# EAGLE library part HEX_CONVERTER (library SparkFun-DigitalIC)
74HC4050 Hex Buffer Level Shifter SMD SO016

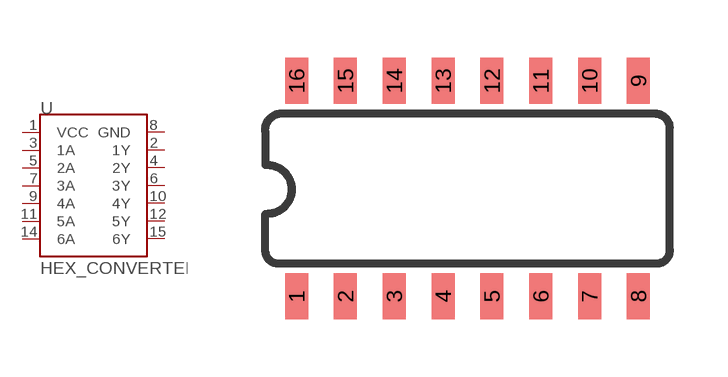
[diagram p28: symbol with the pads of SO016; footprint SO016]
Designator prefix U

## HEX_CONVERTER (PROD_ID: IC-09604)  [SO016]
1  VCC
2  1Y
3  1A
4  2Y
5  2A
6  3Y
7  3A
8  GND
9  4A
10  4Y
11  5A
12  5Y
14  6A
15  6Y

## Footprint SO016 (pad centres in mm)
smd 0.6 x 1.2: 1 -4.445,-2.8; 2 -3.175,-2.8; 3 -1.905,-2.8; 4 -0.635,-2.8; 5 0.635,-2.8; 6 1.905,-2.8; 7 3.175,-2.8; 8 4.445,-2.8; 9 4.445,2.8; 10 3.175,2.8; 11 1.905,2.8; 12 0.635,2.8; 13 -0.635,2.8; 14 -1.905,2.8; 15 -3.175,2.8; 16 -4.445,2.8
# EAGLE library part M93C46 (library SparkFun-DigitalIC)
1kbit SPI EEPROM

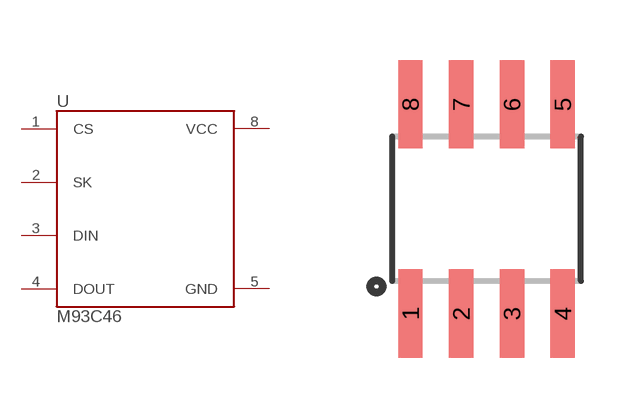
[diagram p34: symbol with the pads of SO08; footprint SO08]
Designator prefix -

## M93C46  [SO08]
1  CS
2  SK
3  DIN
4  DOUT
5  GND
8  VCC

## Footprint SO08 (pad centres in mm)
Small Outline Package Fits JEDEC packages (narrow SOIC-8)
smd 0.61 x 2.21: 1 -1.905,-2.616; 2 -0.635,-2.616; 3 0.635,-2.616; 4 1.905,-2.616; 5 1.905,2.616; 6 0.635,2.616; 7 -0.635,2.616; 8 -1.905,2.616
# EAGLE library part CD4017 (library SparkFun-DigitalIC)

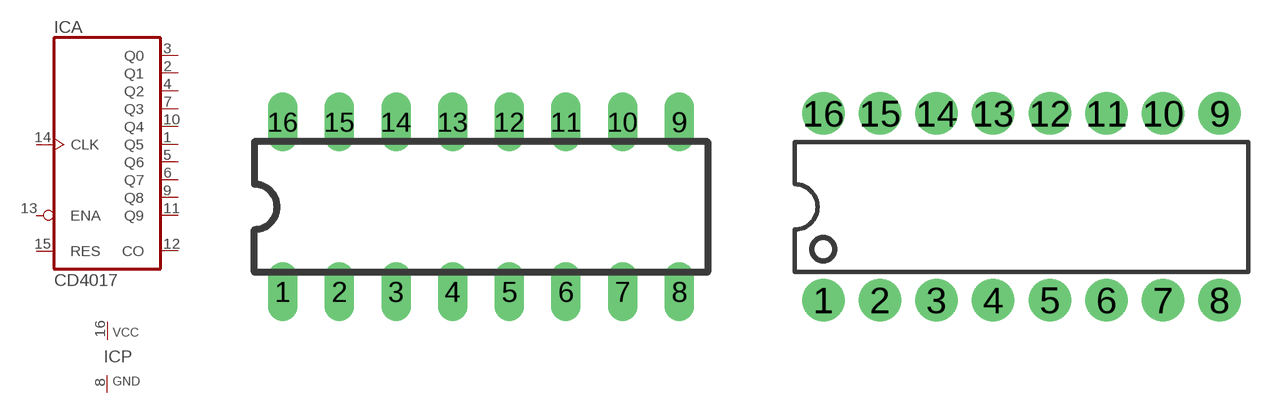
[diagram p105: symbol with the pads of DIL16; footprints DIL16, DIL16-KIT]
Designator prefix IC; gates A=CD4017 P=PWRN

## CD4017 (PROD_ID: IC-11929; VALUE: CD4017)  [DIL16]
1  A:Q5  out
2  A:Q1  out
3  A:Q0  out
4  A:Q2  out
5  A:Q6  out
6  A:Q7  out
7  A:Q3  out
8  P:GND  pwr
9  A:Q8  out
10  A:Q4  out
11  A:Q9  out
12  A:CO  out
13  A:ENA  in
14  A:CLK  in
15  A:RES  in
16  P:VCC  pwr

## CD4017KIT (PROD_ID: IC-11929)  [DIL16-KIT]
Pads as for DIL16

## Footprint DIL16 (pad centres in mm)
Dual In Line Package
drill 0.813 long: 1 -8.89,-3.81; 2 -6.35,-3.81; 3 -3.81,-3.81; 4 -1.27,-3.81; 5 1.27,-3.81; 6 3.81,-3.81; 7 6.35,-3.81; 8 8.89,-3.81; 9 8.89,3.81; 10 6.35,3.81; 11 3.81,3.81; 12 1.27,3.81; 13 -1.27,3.81; 14 -3.81,3.81; 15 -6.35,3.81; 16 -8.89,3.81

## Footprint DIL16-KIT (pad centres in mm)
drill 0.864 pad 1.905: 1 -8.89,-4.191; 2 -6.35,-4.191; 3 -3.81,-4.191; 4 -1.27,-4.191; 5 1.27,-4.191; 6 3.81,-4.191; 7 6.35,-4.191; 8 8.89,-4.191; 9 8.89,4.191; 10 6.35,4.191; 11 3.81,4.191; 12 1.27,4.191; 13 -1.27,4.191; 14 -3.81,4.191; 15 -6.35,4.191; 16 -8.89,4.191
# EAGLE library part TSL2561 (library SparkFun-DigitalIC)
TSL2561 illumination sensor Approximates Human Eye Response Precisely Measures Illuminance Programmable Interrupt Function with User-Defined Upper and Lower Threshold 400 KHz I2C interface Programmable Analog Gain and Integration Time Supporting 1,000,000-to-1 Dynamic Range Automatically Rejects 50/60-Hz Lighting Ripple Low Active Power (0.75 mW Typical) with Power Down Mode RoHS Compliant The TSL2561 is a light-to-digital converter that transform light intensity to a digital signal output via I2C interface. The device combines one broadband photodiode (visible plus infrared) and one infrared-responding photodiode on a single CMOS integrated circuit capable of providing a near-photopic response over an effective 20-bit dynamic range (16-bit resolution). Two integrating ADCs convert the photodiode currents to a digital output that represents the irradiance measured on each channel. This digital output can be input to a microprocessor where illuminance (ambient light level) in lux is derived using an empirical formula to approximate the human eye response. The TSL2561 device supports a traditional level style interrupt that remains asserted until the firmware clears it.

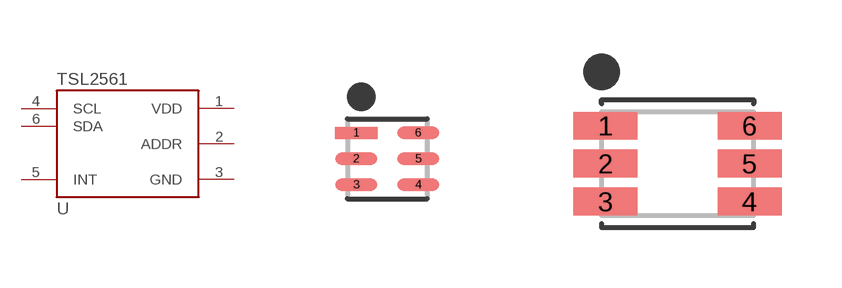
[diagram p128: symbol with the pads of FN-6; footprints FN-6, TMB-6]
Designator prefix U

## TSL2561FN (PROD_ID: IC-11791)  [FN-6]
1  VDD  pwr
2  ADDR  in
3  GND  pwr
4  SCL  in
5  INT  out
6  SDA

## TSL2561T  [TMB-6]
Pads as for FN-6

## Footprint FN-6 (pad centres in mm)
smd 1.05 x 0.3: 1 -0.775,0.65; 2 -0.775,0; 3 -0.775,-0.65; 4 0.775,-0.65; 5 0.775,0; 6 0.775,0.65

## Footprint TMB-6 (pad centres in mm)
smd 1.6 x 0.7: 1 -1.8,0.95; 2 -1.8,0; 3 -1.8,-0.95; 4 1.8,-0.95; 5 1.8,0; 6 1.8,0.95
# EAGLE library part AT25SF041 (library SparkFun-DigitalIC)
SPI Serial flash memory with dual/quad-IO support

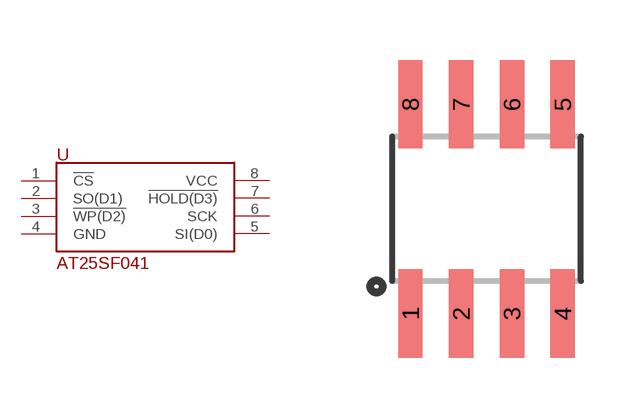
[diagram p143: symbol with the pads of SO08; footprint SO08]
Designator prefix -

## AT25SF041 (PROD_ID: IC-12455; VALUE: AT25SF041-SOIC8)  [SO08]
1  !CS
2  SO(D1)
3  !WP(D2)
4  GND
5  SI(D0)
6  SCK
7  !HOLD(D3)
8  VCC

## Footprint SO08 (pad centres in mm)
Small Outline Package Fits JEDEC packages (narrow SOIC-8)
smd 0.61 x 2.21: 1 -1.905,-2.616; 2 -0.635,-2.616; 3 0.635,-2.616; 4 1.905,-2.616; 5 1.905,2.616; 6 0.635,2.616; 7 -0.635,2.616; 8 -1.905,2.616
